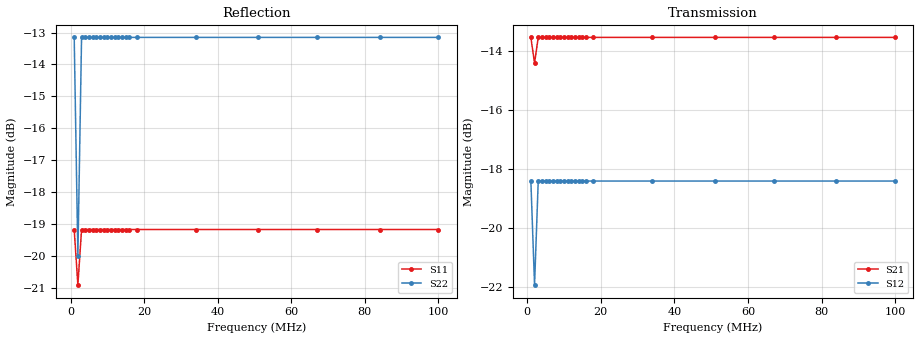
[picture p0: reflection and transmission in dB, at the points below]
# MHz S RI R 50
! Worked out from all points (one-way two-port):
!   100 points, 1 MHz to 100 MHz, reference 50 ohm
!   highest |S21| = -13.56 dB at 1 MHz (marker M1); lowest = -14.4 dB at 2 MHz (marker M2)
!   lowest |S11| = -20.9 dB at 2 MHz (marker M3), VSWR 1.20, Z = 59.9 + j0 ohm
!   |S11| at or under -10 dB: start of sweep to end of sweep
!   |S22| runs from -20.0 to -13.2 dB; largest |S21 - S12| = 0.11
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1  0.11 0  0.21 0  0.12 0  0.22 0
2  0.09 0  0.19 0  0.08 0  0.1 0
3  0.11 0  0.21 0  0.12 0  0.22 0
4  0.11 0  0.21 0  0.12 0  0.22 0
5  0.11 0  0.21 0  0.12 0  0.22 0
6  0.11 0  0.21 0  0.12 0  0.22 0
7  0.11 0  0.21 0  0.12 0  0.22 0
8  0.11 0  0.21 0  0.12 0  0.22 0
9  0.11 0  0.21 0  0.12 0  0.22 0
10  0.11 0  0.21 0  0.12 0  0.22 0
11  0.11 0  0.21 0  0.12 0  0.22 0
12  0.11 0  0.21 0  0.12 0  0.22 0
13  0.11 0  0.21 0  0.12 0  0.22 0
14  0.11 0  0.21 0  0.12 0  0.22 0
15  0.11 0  0.21 0  0.12 0  0.22 0
16  0.11 0  0.21 0  0.12 0  0.22 0
18  0.11 0  0.21 0  0.12 0  0.22 0
34  0.11 0  0.21 0  0.12 0  0.22 0
51  0.11 0  0.21 0  0.12 0  0.22 0
67  0.11 0  0.21 0  0.12 0  0.22 0
84  0.11 0  0.21 0  0.12 0  0.22 0
100  0.11 0  0.21 0  0.12 0  0.22 0
